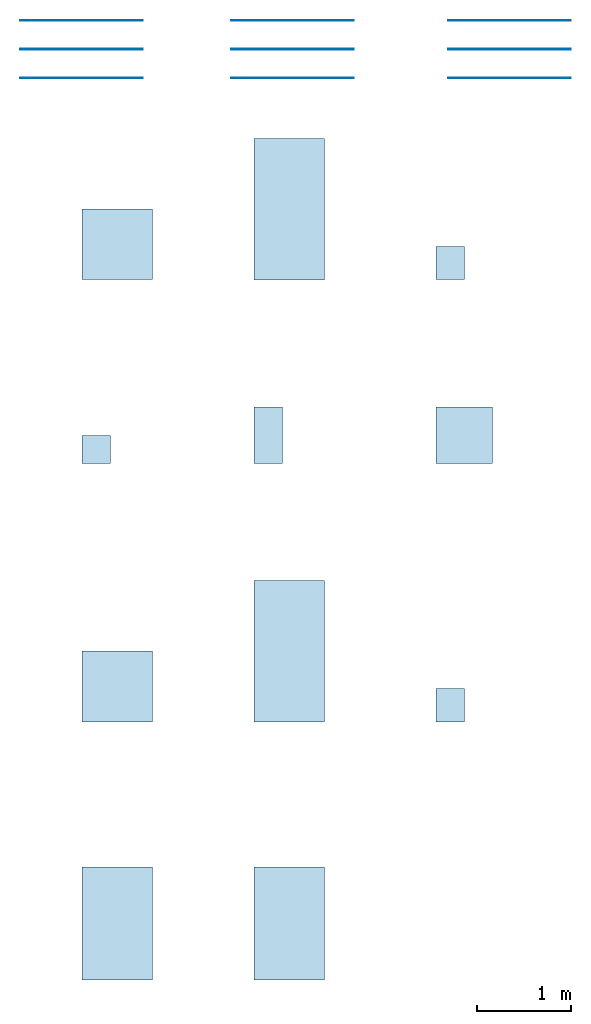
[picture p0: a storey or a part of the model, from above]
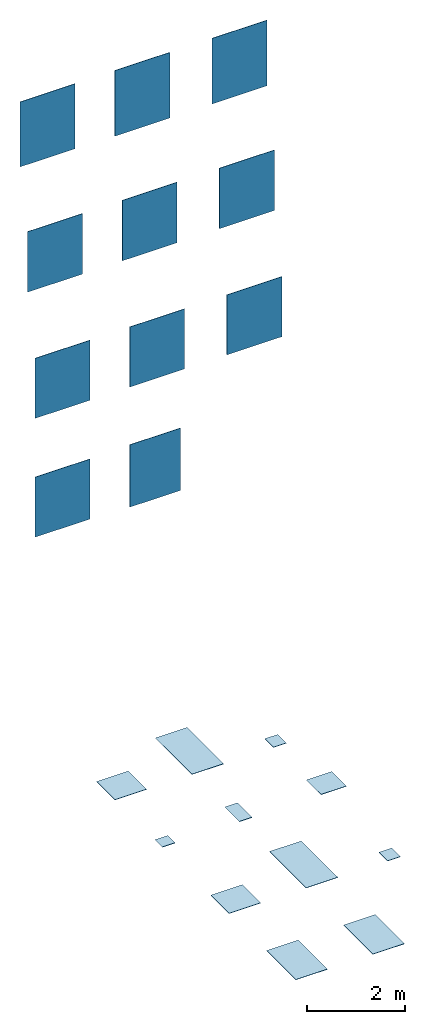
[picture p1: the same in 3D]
Properties of the parts of a building model (IFC2X3)

# File
Description: ViewDefinition [CoordinationView_V2.0], RevitIdentifiers [VersionGUID: 78f5554a-610e-4848-a1b2-b2670045736c, NumberOfSaves: 284], CoordinateReference [CoordinateBase: Shared Coordinates, ProjectSite: Internal]
File name: Project Number
Time: 2025-02-25T11:23:09+01:00
Written by: ODA SDAI 24.3
Made in: Autodesk Revit 24.1.11.26 (ENU) - IFC 24.1.11.26

# IfcProject, Project Number
LongName: Refin-Blended; Phase: Project Status

# IfcSite, Default
RefLatitude: 51, 30, 0, 549316; RefLongitude: 0, -7, -34, -450321; RefElevation: 0 mm

# IfcBuilding
Pset_BuildingCommon - NumberOfStoreys: 1

# IfcBuildingStorey: Level:Circle Head - Project Datum (2)
Pset_AirSideSystemInformation - sets with these values: 2
Name | LongName = Name | Elevation (mm)
Level 0 | Level 0 | 0
Level 1 | Level 1 | 4000

# IfcSlab: Floor:Floor_Tiles_Refin-Prestigio_Travertino-Bianco-Lucido-75x75 OO02, Floor:Floor_Tiles_Refin-Prestigio_Travertino-Bianco-Lucido-75x75 OO02:304668
In: Level 0
Type - PredefinedType: FLOOR; Material: Prestigio Travertino-Bianco-Lucido-75x75 OO02 9 mm, <Unnamed> 1 mm
Type - Pset_ConcreteElementGeneral - FireRating: INERT
Type - Pset_ElementShading - Color: WHITE
Type - Pset_FireRatingProperties - SurfaceSpreadOfFlame: INERT
Type - Pset_ManufacturerOccurrence - BarCode: N/A; SerialNumber: N/A
Type - Pset_ManufacturerTypeInformation - ArticleNumber: OO02; ModelReference: OO02; ModelLabel: BIANCO LUCIDO 75X75; Manufacturer: info@refin.it; ProductionYear: N/A
Type - Pset_PrecastConcreteElementGeneral - SerialNumber: N/A
Type - Pset_ProductRequirements - Name: Prestigio_Travertino_Bianco_Lucido_75X75; Category: Pr_35_93_96_19:Ceramic tiles
Type - Pset_QuantityTakeOff - Reference: N/A
Type - Pset_ReinforcementBarPitchOfSlab - Description: PORCELAIN STONEWARE TILE; Reference: N/A
Type - Pset_SlabCommon - Reference: N/A; IsExternal: no; AcousticRating: N/A; FireRating: INERT; SurfaceSpreadOfFlame: INERT
Type - Pset_Warranty - WarrantyContent: N/A; Exclusions: N/A
Pset_QuantityTakeOff - sets with these values: 2
Pset_SlabCommon - LoadBearing: no; PitchAngle: 0 deg

# IfcSlab: Floor:Floor_Tiles_Refin-Prestigio_Travertino-Bianco-Lucido-Mosaico-Cube 30.4x35.2 OO31, Floor:Floor_Tiles_Refin-Prestigio_Travertino-Bianco-Lucido-Mosaico-Cube 30.4x35.2 OO31:285295
In: Level 0
Type - PredefinedType: FLOOR; Material: Prestigio Travertino-Bianco-Lucido-Mosaico-Cube 30.4x35.2 OO31 9 mm, <Unnamed> 1 mm
Type - Pset_ConcreteElementGeneral - FireRating: INERT
Type - Pset_ElementShading - Color: WHITE
Type - Pset_FireRatingProperties - SurfaceSpreadOfFlame: INERT
Type - Pset_ManufacturerOccurrence - BarCode: N/A; SerialNumber: N/A
Type - Pset_ManufacturerTypeInformation - ArticleNumber: OO31; ModelReference: OO31; ModelLabel: BIANCO LUCIDO MOSAICO CUBE 30.4X35.2; Manufacturer: info@refin.it; ProductionYear: N/A
Type - Pset_PrecastConcreteElementGeneral - SerialNumber: N/A
Type - Pset_ProductRequirements - Name: Prestigio_Travertino_Bianco_Lucido_Mosaico_Cube_30.4X35.2; Category: Pr_35_93_96_19:Ceramic tiles
Type - Pset_QuantityTakeOff - Reference: N/A
Type - Pset_ReinforcementBarPitchOfSlab - Description: PORCELAIN STONEWARE TILE; Reference: N/A
Type - Pset_SlabCommon - Reference: N/A; IsExternal: no; AcousticRating: N/A; FireRating: INERT; SurfaceSpreadOfFlame: INERT
Type - Pset_Warranty - WarrantyContent: N/A; Exclusions: N/A
Pset_QuantityTakeOff - sets with these values: 2
Pset_SlabCommon - LoadBearing: no; PitchAngle: 0 deg

# IfcSlab: Floor:Floor_Tiles_Refin-Prestigio_Travertino-Bianco-Lucido-Mosaico-T 30x30 OO37, Floor:Floor_Tiles_Refin-Prestigio_Travertino-Bianco-Lucido-Mosaico-T 30x30 OO37:304956
In: Level 0
Type - PredefinedType: FLOOR; Material: Prestigio Travertino-Bianco-Mix-Mosaico-T 30x30 OO37 9 mm, <Unnamed> 1 mm
Type - Pset_ConcreteElementGeneral - FireRating: INERT
Type - Pset_ElementShading - Color: WHITE
Type - Pset_FireRatingProperties - SurfaceSpreadOfFlame: INERT
Type - Pset_ManufacturerOccurrence - BarCode: N/A; SerialNumber: N/A
Type - Pset_ManufacturerTypeInformation - ArticleNumber: OO37; ModelReference: OO37; ModelLabel: BIANCO MIX MOSAICO T 3X30; Manufacturer: info@refin.it; ProductionYear: N/A
Type - Pset_PrecastConcreteElementGeneral - SerialNumber: N/A
Type - Pset_ProductRequirements - Name: Prestigio_Travertino_Bianco_Mix_Mosaico_T_3X30; Category: Pr_35_93_96_19:Ceramic tiles
Type - Pset_QuantityTakeOff - Reference: N/A
Type - Pset_ReinforcementBarPitchOfSlab - Description: PORCELAIN STONEWARE TILE; Reference: N/A
Type - Pset_SlabCommon - Reference: N/A; IsExternal: no; AcousticRating: N/A; FireRating: INERT; SurfaceSpreadOfFlame: INERT
Type - Pset_Warranty - WarrantyContent: N/A; Exclusions: N/A
Pset_QuantityTakeOff - sets with these values: 2
Pset_SlabCommon - LoadBearing: no; PitchAngle: 0 deg

# IfcSlab: Floor:Floor_Tiles_Refin-Prestigio_Travertino-Bianco-Soft-30x60 OO08, Floor:Floor_Tiles_Refin-Prestigio_Travertino-Bianco-Soft-30x60 OO08:304948
In: Level 0
Type - PredefinedType: FLOOR; Material: Prestigio Travertino-Bianco-Soft-30x60 OO08 9 mm, <Unnamed> 1 mm
Type - Pset_ConcreteElementGeneral - FireRating: INERT
Type - Pset_ElementShading - Color: WHITE
Type - Pset_FireRatingProperties - SurfaceSpreadOfFlame: INERT
Type - Pset_ManufacturerOccurrence - BarCode: N/A; SerialNumber: N/A
Type - Pset_ManufacturerTypeInformation - ArticleNumber: OO08; ModelReference: OO08; ModelLabel: BIANCO SOFT 30X60; Manufacturer: info@refin.it; ProductionYear: N/A
Type - Pset_PrecastConcreteElementGeneral - SerialNumber: N/A
Type - Pset_ProductRequirements - Name: Prestigio_Travertino_Bianco_Soft_30X60; Category: Pr_35_93_96_19:Ceramic tiles
Type - Pset_QuantityTakeOff - Reference: N/A
Type - Pset_ReinforcementBarPitchOfSlab - Description: PORCELAIN STONEWARE TILE; Reference: N/A
Type - Pset_SlabCommon - Reference: N/A; IsExternal: no; AcousticRating: N/A; FireRating: INERT; SurfaceSpreadOfFlame: INERT
Type - Pset_Warranty - WarrantyContent: N/A; Exclusions: N/A
Pset_QuantityTakeOff - sets with these values: 2
Pset_SlabCommon - LoadBearing: no; PitchAngle: 0 deg

# IfcSlab: Floor:Floor_Tiles_Refin-Prestigio_Travertino-Bianco-Soft-60x120 OZ36, Floor:Floor_Tiles_Refin-Prestigio_Travertino-Bianco-Soft-60x120 OZ36:348918
In: Level 0
Type - PredefinedType: FLOOR; Material: Prestigio Travertino-Bianco-Soft-60x120 OZ36 9 mm, <Unnamed> 1 mm
Type - Pset_ConcreteElementGeneral - FireRating: INERT
Type - Pset_ElementShading - Color: WHITE
Type - Pset_FireRatingProperties - SurfaceSpreadOfFlame: INERT
Type - Pset_ManufacturerOccurrence - BarCode: N/A; SerialNumber: N/A
Type - Pset_ManufacturerTypeInformation - ArticleNumber: OZ36; ModelReference: OZ36; ModelLabel: BIANCO SOFT 60X120; Manufacturer: info@refin.it; ProductionYear: N/A
Type - Pset_PrecastConcreteElementGeneral - SerialNumber: N/A
Type - Pset_ProductRequirements - Name: Prestigio_Travertino_Bianco_Soft_60X120; Category: Pr_35_93_96_19:Ceramic tiles
Type - Pset_QuantityTakeOff - Reference: N/A
Type - Pset_ReinforcementBarPitchOfSlab - Description: PORCELAIN STONEWARE TILE; Reference: N/A
Type - Pset_SlabCommon - Reference: N/A; IsExternal: no; AcousticRating: N/A; FireRating: INERT; SurfaceSpreadOfFlame: INERT
Type - Pset_Warranty - WarrantyContent: N/A; Exclusions: N/A
Pset_QuantityTakeOff - sets with these values: 2
Pset_SlabCommon - LoadBearing: no; PitchAngle: 0 deg

# IfcSlab: Floor:Floor_Tiles_Refin-Prestigio_Travertino-Bianco-Soft-60x60 OO05, Floor:Floor_Tiles_Refin-Prestigio_Travertino-Bianco-Soft-60x60 OO05:304932
In: Level 0
Type - PredefinedType: FLOOR; Material: Prestigio Travertino-Bianco-Soft-60x60 OO05 9 mm, <Unnamed> 1 mm
Type - Pset_ConcreteElementGeneral - FireRating: INERT
Type - Pset_ElementShading - Color: WHITE
Type - Pset_FireRatingProperties - SurfaceSpreadOfFlame: INERT
Type - Pset_ManufacturerOccurrence - BarCode: N/A; SerialNumber: N/A
Type - Pset_ManufacturerTypeInformation - ArticleNumber: OO05; ModelReference: OO05; ModelLabel: BIANCO SOFT 60X60; Manufacturer: info@refin.it; ProductionYear: N/A
Type - Pset_PrecastConcreteElementGeneral - SerialNumber: N/A
Type - Pset_ProductRequirements - Name: Prestigio_Travertino_Bianco_Soft_60X60; Category: Pr_35_93_96_19:Ceramic tiles
Type - Pset_QuantityTakeOff - Reference: N/A
Type - Pset_ReinforcementBarPitchOfSlab - Description: PORCELAIN STONEWARE TILE; Reference: N/A
Type - Pset_SlabCommon - Reference: N/A; IsExternal: no; AcousticRating: N/A; FireRating: INERT; SurfaceSpreadOfFlame: INERT
Type - Pset_Warranty - WarrantyContent: N/A; Exclusions: N/A
Pset_QuantityTakeOff - sets with these values: 2
Pset_SlabCommon - LoadBearing: no; PitchAngle: 0 deg

# IfcSlab: Floor:Floor_Tiles_Refin-Prestigio_Travertino-Bianco-Soft-75x150 OM84, Floor:Floor_Tiles_Refin-Prestigio_Travertino-Bianco-Soft-75x150 OM84:339635
In: Level 0
Type - PredefinedType: FLOOR; Material: Prestigio Travertino-Bianco-Soft-75x150 OM84 9 mm, <Unnamed> 1 mm
Type - Pset_ConcreteElementGeneral - FireRating: INERT
Type - Pset_ElementShading - Color: WHITE
Type - Pset_FireRatingProperties - SurfaceSpreadOfFlame: INERT
Type - Pset_ManufacturerOccurrence - BarCode: N/A; SerialNumber: N/A
Type - Pset_ManufacturerTypeInformation - ArticleNumber: OM84; ModelReference: OM84; ModelLabel: BIANCO SOFT 75X150; Manufacturer: info@refin.it; ProductionYear: N/A
Type - Pset_PrecastConcreteElementGeneral - SerialNumber: N/A
Type - Pset_ProductRequirements - Name: Prestigio_Travertino_Bianco_Soft_75X150; Category: Pr_35_93_96_19:Ceramic tiles
Type - Pset_QuantityTakeOff - Reference: N/A
Type - Pset_ReinforcementBarPitchOfSlab - Description: PORCELAIN STONEWARE TILE; Reference: N/A
Type - Pset_SlabCommon - Reference: N/A; IsExternal: no; AcousticRating: N/A; FireRating: INERT; SurfaceSpreadOfFlame: INERT
Type - Pset_Warranty - WarrantyContent: N/A; Exclusions: N/A
Pset_QuantityTakeOff - sets with these values: 2
Pset_SlabCommon - LoadBearing: no; PitchAngle: 0 deg

# IfcSlab: Floor:Floor_Tiles_Refin-Prestigio_Travertino-Bianco-Soft-75x150 OM87, Floor:Floor_Tiles_Refin-Prestigio_Travertino-Bianco-Soft-75x150 OM87:324498
In: Level 0
Type - PredefinedType: FLOOR; Material: Prestigio Travertino-Bianco-Lucido-75x150 OM87 9 mm, <Unnamed> 1 mm
Type - Pset_ConcreteElementGeneral - FireRating: INERT
Type - Pset_ElementShading - Color: WHITE
Type - Pset_FireRatingProperties - SurfaceSpreadOfFlame: INERT
Type - Pset_ManufacturerOccurrence - BarCode: N/A; SerialNumber: N/A
Type - Pset_ManufacturerTypeInformation - ArticleNumber: OM87; ModelReference: OM87; ModelLabel: BIANCO LUCIDO 75X150; Manufacturer: info@refin.it; ProductionYear: N/A
Type - Pset_PrecastConcreteElementGeneral - SerialNumber: N/A
Type - Pset_ProductRequirements - Name: Prestigio_Travertino_Bianco_Lucido_75X150; Category: Pr_35_93_96_19:Ceramic tiles
Type - Pset_QuantityTakeOff - Reference: N/A
Type - Pset_ReinforcementBarPitchOfSlab - Description: PORCELAIN STONEWARE TILE; Reference: N/A
Type - Pset_SlabCommon - Reference: N/A; IsExternal: no; AcousticRating: N/A; FireRating: INERT; SurfaceSpreadOfFlame: INERT
Type - Pset_Warranty - WarrantyContent: N/A; Exclusions: N/A
Pset_QuantityTakeOff - sets with these values: 2
Pset_SlabCommon - LoadBearing: no; PitchAngle: 0 deg

# IfcSlab: Floor:Floor_Tiles_Refin-Prestigio_Travertino-Bianco-Soft-75x75 ON99, Floor:Floor_Tiles_Refin-Prestigio_Travertino-Bianco-Soft-75x75 ON99:305509
In: Level 0
Type - PredefinedType: FLOOR; Material: Prestigio Travertino-Bianco-Soft-75x75 ON99 9 mm, <Unnamed> 1 mm
Type - Pset_ConcreteElementGeneral - FireRating: INERT
Type - Pset_ElementShading - Color: WHITE
Type - Pset_FireRatingProperties - SurfaceSpreadOfFlame: INERT
Type - Pset_ManufacturerOccurrence - BarCode: N/A; SerialNumber: N/A
Type - Pset_ManufacturerTypeInformation - ArticleNumber: ON99; ModelReference: ON99; ModelLabel: BIANCO SOFT 75X75; Manufacturer: info@refin.it; ProductionYear: N/A
Type - Pset_PrecastConcreteElementGeneral - SerialNumber: N/A
Type - Pset_ProductRequirements - Name: Prestigio_Travertino_Bianco_Soft_75X75; Category: Pr_35_93_96_19:Ceramic tiles
Type - Pset_QuantityTakeOff - Reference: N/A
Type - Pset_ReinforcementBarPitchOfSlab - Description: PORCELAIN STONEWARE TILE; Reference: N/A
Type - Pset_SlabCommon - Reference: N/A; IsExternal: no; AcousticRating: N/A; FireRating: INERT; SurfaceSpreadOfFlame: INERT
Type - Pset_Warranty - WarrantyContent: N/A; Exclusions: N/A
Pset_QuantityTakeOff - sets with these values: 2
Pset_SlabCommon - LoadBearing: no; PitchAngle: 0 deg

# IfcSlab: Floor:Floor_Tiles_Refin-Prestigio_Travertino-Bianco-Soft-Mosaico-Cube 30.4x35.2 OO34, Floor:Floor_Tiles_Refin-Prestigio_Travertino-Bianco-Soft-Mosaico-Cube 30.4x35.2 OO34:339650
In: Level 0
Type - PredefinedType: FLOOR; Material: Prestigio Travertino-Bianco-Soft-Mosaico-Cube 30.4x35.2 OO34 9 mm, <Unnamed> 1 mm
Type - Pset_ConcreteElementGeneral - FireRating: INERT
Type - Pset_ElementShading - Color: WHITE
Type - Pset_FireRatingProperties - SurfaceSpreadOfFlame: INERT
Type - Pset_ManufacturerOccurrence - BarCode: N/A; SerialNumber: N/A
Type - Pset_ManufacturerTypeInformation - ArticleNumber: OO34; ModelReference: OO34; ModelLabel: BIANCO SOFT MOSAICO CUBE 30.4X35.2; Manufacturer: info@refin.it; ProductionYear: N/A
Type - Pset_PrecastConcreteElementGeneral - SerialNumber: N/A
Type - Pset_ProductRequirements - Name: Prestigio_Travertino_Bianco_Soft_Mosaico_Cube_30.4X35.2; Category: Pr_35_93_96_19:Ceramic tiles
Type - Pset_QuantityTakeOff - Reference: N/A
Type - Pset_ReinforcementBarPitchOfSlab - Description: PORCELAIN STONEWARE TILE; Reference: N/A
Type - Pset_SlabCommon - Reference: N/A; IsExternal: no; AcousticRating: N/A; FireRating: INERT; SurfaceSpreadOfFlame: INERT
Type - Pset_Warranty - WarrantyContent: N/A; Exclusions: N/A
Pset_QuantityTakeOff - sets with these values: 2
Pset_SlabCommon - LoadBearing: no; PitchAngle: 0 deg

# IfcSlab: Floor:Floor_Tiles_Refin-Prestigio_Travertino-Dorico-Bianco-60x120 OZ79, Floor:Floor_Tiles_Refin-Prestigio_Travertino-Dorico-Bianco-60x120 OZ79:349322
In: Level 0
Type - PredefinedType: FLOOR; Material: Prestigio Travertino-Dorico-Bianco-60x120 OZ79 9 mm, <Unnamed> 1 mm
Type - Pset_ConcreteElementGeneral - FireRating: INERT
Type - Pset_ElementShading - Color: WHITE
Type - Pset_FireRatingProperties - SurfaceSpreadOfFlame: INERT
Type - Pset_ManufacturerOccurrence - BarCode: N/A; SerialNumber: N/A
Type - Pset_ManufacturerTypeInformation - ArticleNumber: OZ79; ModelReference: OZ79; ModelLabel: DORICO BIANCO 60X120; Manufacturer: info@refin.it; ProductionYear: N/A
Type - Pset_PrecastConcreteElementGeneral - SerialNumber: N/A
Type - Pset_ProductRequirements - Name: Prestigio_Travertino_Dorico_Bianco_60X120; Category: Pr_35_93_96_19:Ceramic tiles
Type - Pset_QuantityTakeOff - Reference: N/A
Type - Pset_ReinforcementBarPitchOfSlab - Description: PORCELAIN STONEWARE TILE; Reference: N/A
Type - Pset_SlabCommon - Reference: N/A; IsExternal: no; AcousticRating: N/A; FireRating: INERT; SurfaceSpreadOfFlame: INERT
Type - Pset_Warranty - WarrantyContent: N/A; Exclusions: N/A
Pset_QuantityTakeOff - sets with these values: 2
Pset_SlabCommon - LoadBearing: no; PitchAngle: 0 deg

# IfcWallStandardCase: Basic Wall:Floor_Tiles_Refin-Prestigio_Travertino-Bianco-Lucido-75x150 OM87, Basic Wall:Floor_Tiles_Refin-Prestigio_Travertino-Bianco-Lucido-75x150 OM87:333696
In: Level 0
Type - PredefinedType: STANDARD; Material: <Unnamed> 1 mm, Prestigio Travertino-Bianco-Lucido-75x150 OM87 9 mm
Type - Pset_ElementShading - Color: WHITE
Type - Pset_FireRatingProperties - SurfaceSpreadOfFlame: INERT
Type - Pset_ManufacturerOccurrence - BarCode: N/A; SerialNumber: N/A
Type - Pset_ManufacturerTypeInformation - ArticleNumber: OM87; ModelReference: OM87; ModelLabel: BIANCO LUCIDO 75X150; Manufacturer: info@refin.it; ProductionYear: N/A
Type - Pset_PrecastConcreteElementGeneral - SerialNumber: N/A
Type - Pset_ProductRequirements - Name: Prestigio Travertino_Bianco_Lucido_75X150; Category: Pr_35_93_96_19:Ceramic tiles
Type - Pset_QuantityTakeOff - Reference: N/A
Type - Pset_ReinforcementBarPitchOfWall - Description: PORCELAIN STONEWARE TILE; Reference: N/A
Type - Pset_WallCommon - Reference: N/A; IsExternal: no; AcousticRating: N/A; SurfaceSpreadOfFlame: INERT
Type - Pset_Warranty - WarrantyContent: N/A; Exclusions: N/A
Pset_QuantityTakeOff - sets with these values: 2
Pset_WallCommon - LoadBearing: no; ExtendToStructure: no

# IfcWallStandardCase: Basic Wall:Floor_Tiles_Refin-Prestigio_Travertino-Bianco-Lucido-75x75 OO02, Basic Wall:Floor_Tiles_Refin-Prestigio_Travertino-Bianco-Lucido-75x75 OO02:334895
In: Level 0
Type - PredefinedType: STANDARD; Material: <Unnamed> 1 mm, Prestigio Travertino-Bianco-Lucido-75x75 OO02 9 mm
Type - Pset_ElementShading - Color: WHITE
Type - Pset_FireRatingProperties - SurfaceSpreadOfFlame: INERT
Type - Pset_ManufacturerOccurrence - BarCode: N/A; SerialNumber: N/A
Type - Pset_ManufacturerTypeInformation - ArticleNumber: OO02; ModelReference: OO02; ModelLabel: BIANCO LUCIDO 75X75; Manufacturer: info@refin.it; ProductionYear: N/A
Type - Pset_PrecastConcreteElementGeneral - SerialNumber: N/A
Type - Pset_ProductRequirements - Name: Prestigio Travertino_Bianco_Lucido_75X75; Category: Pr_35_93_96_19:Ceramic tiles
Type - Pset_QuantityTakeOff - Reference: N/A
Type - Pset_ReinforcementBarPitchOfWall - Description: PORCELAIN STONEWARE TILE; Reference: N/A
Type - Pset_WallCommon - Reference: N/A; IsExternal: no; AcousticRating: N/A; SurfaceSpreadOfFlame: INERT
Type - Pset_Warranty - WarrantyContent: N/A; Exclusions: N/A
Pset_QuantityTakeOff - sets with these values: 2
Pset_WallCommon - LoadBearing: no; ExtendToStructure: no

# IfcWallStandardCase: Basic Wall:Floor_Tiles_Refin-Prestigio_Travertino-Bianco-Lucido-Mosaico-Cube 30.4x35.2 OO31, Basic Wall:Floor_Tiles_Refin-Prestigio_Travertino-Bianco-Lucido-Mosaico-Cube 30.4x35.2 OO31:334553
In: Level 0
Type - PredefinedType: STANDARD; Material: <Unnamed> 1 mm, Prestigio Travertino-Bianco-Lucido-Mosaico-Cube 30.4x35.2 OO31 9 mm
Type - Pset_ElementShading - Color: WHITE
Type - Pset_FireRatingProperties - SurfaceSpreadOfFlame: INERT
Type - Pset_ManufacturerOccurrence - BarCode: N/A; SerialNumber: N/A
Type - Pset_ManufacturerTypeInformation - ArticleNumber: OO31; ModelReference: OO31; ModelLabel: BIANCO LUCIDO MOSAICO CUBE 30.4X35.2; Manufacturer: info@refin.it; ProductionYear: N/A
Type - Pset_PrecastConcreteElementGeneral - SerialNumber: N/A
Type - Pset_ProductRequirements - Name: Prestigio Travertino_Bianco_Lucido_Mosaico_Cube_30.4X35.2; Category: Pr_35_93_96_19:Ceramic tiles
Type - Pset_QuantityTakeOff - Reference: N/A
Type - Pset_ReinforcementBarPitchOfWall - Description: PORCELAIN STONEWARE TILE; Reference: N/A
Type - Pset_WallCommon - Reference: N/A; IsExternal: no; AcousticRating: N/A; SurfaceSpreadOfFlame: INERT
Type - Pset_Warranty - WarrantyContent: N/A; Exclusions: N/A
Pset_QuantityTakeOff - sets with these values: 2
Pset_WallCommon - LoadBearing: no; ExtendToStructure: no

# IfcWallStandardCase: Basic Wall:Floor_Tiles_Refin-Prestigio_Travertino-Bianco-Lucido-Mosaico-T 30x30 OO37, Basic Wall:Floor_Tiles_Refin-Prestigio_Travertino-Bianco-Lucido-Mosaico-T 30x30 OO37:335038
In: Level 0
Type - PredefinedType: STANDARD; Material: <Unnamed> 1 mm, Prestigio Travertino-Bianco-Mix-Mosaico-T 30x30 OO37 9 mm
Type - Pset_ElementShading - Color: WHITE
Type - Pset_FireRatingProperties - SurfaceSpreadOfFlame: INERT
Type - Pset_ManufacturerOccurrence - BarCode: N/A; SerialNumber: N/A
Type - Pset_ManufacturerTypeInformation - ArticleNumber: OO37; ModelReference: OO37; ModelLabel: BIANCO MIX MOSAICO T 30X30; Manufacturer: info@refin.it; ProductionYear: N/A
Type - Pset_PrecastConcreteElementGeneral - SerialNumber: N/A
Type - Pset_ProductRequirements - Name: Prestigio Travertino_Bianco_Mix_Mosaico_T_30X30; Category: Pr_35_93_96_19:Ceramic tiles
Type - Pset_QuantityTakeOff - Reference: N/A
Type - Pset_ReinforcementBarPitchOfWall - Description: PORCELAIN STONEWARE TILE; Reference: N/A
Type - Pset_WallCommon - Reference: N/A; IsExternal: no; AcousticRating: N/A; SurfaceSpreadOfFlame: INERT
Type - Pset_Warranty - WarrantyContent: N/A; Exclusions: N/A
Pset_QuantityTakeOff - sets with these values: 2
Pset_WallCommon - LoadBearing: no; ExtendToStructure: no

# IfcWallStandardCase: Basic Wall:Floor_Tiles_Refin-Prestigio_Travertino-Bianco-Soft-30x60 OO08, Basic Wall:Floor_Tiles_Refin-Prestigio_Travertino-Bianco-Soft-30x60 OO08:335490
In: Level 0
Type - PredefinedType: STANDARD; Material: <Unnamed> 1 mm, Prestigio Travertino-Bianco-Soft-30x60 OO08 9 mm
Type - Pset_ElementShading - Color: WHITE
Type - Pset_FireRatingProperties - SurfaceSpreadOfFlame: INERT
Type - Pset_ManufacturerOccurrence - BarCode: N/A; SerialNumber: N/A
Type - Pset_ManufacturerTypeInformation - ArticleNumber: OO08; ModelReference: OO08; ModelLabel: BIANCO SOFT 30X60; Manufacturer: info@refin.it; ProductionYear: N/A
Type - Pset_PrecastConcreteElementGeneral - SerialNumber: N/A
Type - Pset_ProductRequirements - Name: Prestigio Travertino_Bianco_Soft_30X60; Category: Pr_35_93_96_19:Ceramic tiles
Type - Pset_QuantityTakeOff - Reference: N/A
Type - Pset_ReinforcementBarPitchOfWall - Description: PORCELAIN STONEWARE TILE; Reference: N/A
Type - Pset_WallCommon - Reference: N/A; IsExternal: no; AcousticRating: N/A; SurfaceSpreadOfFlame: INERT
Type - Pset_Warranty - WarrantyContent: N/A; Exclusions: N/A
Pset_QuantityTakeOff - sets with these values: 2
Pset_WallCommon - LoadBearing: no; ExtendToStructure: no

# IfcWallStandardCase: Basic Wall:Floor_Tiles_Refin-Prestigio_Travertino-Bianco-Soft-60x120 OZ36, Basic Wall:Floor_Tiles_Refin-Prestigio_Travertino-Bianco-Soft-60x120 OZ36:348957
In: Level 0
Type - PredefinedType: STANDARD; Material: <Unnamed> 1 mm, Prestigio Travertino-Bianco-Soft-60x120 OZ36 9 mm
Type - Pset_ElementShading - Color: WHITE
Type - Pset_FireRatingProperties - SurfaceSpreadOfFlame: INERT
Type - Pset_ManufacturerOccurrence - BarCode: N/A; SerialNumber: N/A
Type - Pset_ManufacturerTypeInformation - ArticleNumber: OZ36; ModelReference: OZ36; ModelLabel: BIANCO SOFT 60X120; Manufacturer: info@refin.it; ProductionYear: N/A
Type - Pset_PrecastConcreteElementGeneral - SerialNumber: N/A
Type - Pset_ProductRequirements - Name: Prestigio Travertino_Bianco_Soft_60X120; Category: Pr_35_93_96_19:Ceramic tiles
Type - Pset_QuantityTakeOff - Reference: N/A
Type - Pset_ReinforcementBarPitchOfWall - Description: PORCELAIN STONEWARE TILE; Reference: N/A
Type - Pset_WallCommon - Reference: N/A; IsExternal: no; AcousticRating: N/A; SurfaceSpreadOfFlame: INERT
Type - Pset_Warranty - WarrantyContent: N/A; Exclusions: N/A
Pset_QuantityTakeOff - sets with these values: 2
Pset_WallCommon - LoadBearing: no; ExtendToStructure: no

# IfcWallStandardCase: Basic Wall:Floor_Tiles_Refin-Prestigio_Travertino-Bianco-Soft-60x60 OO05, Basic Wall:Floor_Tiles_Refin-Prestigio_Travertino-Bianco-Soft-60x60 OO05:335882
In: Level 0
Type - PredefinedType: STANDARD; Material: <Unnamed> 1 mm, Prestigio Travertino-Bianco-Soft-60x60 OO05 9 mm
Type - Pset_ElementShading - Color: WHITE
Type - Pset_FireRatingProperties - SurfaceSpreadOfFlame: INERT
Type - Pset_ManufacturerOccurrence - BarCode: N/A; SerialNumber: N/A
Type - Pset_ManufacturerTypeInformation - ArticleNumber: OO05; ModelReference: OO05; ModelLabel: BIANCO SOFT 60X60; Manufacturer: info@refin.it; ProductionYear: N/A
Type - Pset_PrecastConcreteElementGeneral - SerialNumber: N/A
Type - Pset_ProductRequirements - Name: Prestigio Travertino_Bianco_Soft_60X60; Category: Pr_35_93_96_19:Ceramic tiles
Type - Pset_QuantityTakeOff - Reference: N/A
Type - Pset_ReinforcementBarPitchOfWall - Description: PORCELAIN STONEWARE TILE; Reference: N/A
Type - Pset_WallCommon - Reference: N/A; IsExternal: no; AcousticRating: N/A; SurfaceSpreadOfFlame: INERT
Type - Pset_Warranty - WarrantyContent: N/A; Exclusions: N/A
Pset_QuantityTakeOff - sets with these values: 2
Pset_WallCommon - LoadBearing: no; ExtendToStructure: no

# IfcWallStandardCase: Basic Wall:Floor_Tiles_Refin-Prestigio_Travertino-Bianco-Soft-75x150 OM84, Basic Wall:Floor_Tiles_Refin-Prestigio_Travertino-Bianco-Soft-75x150 OM84:339715
In: Level 0
Type - PredefinedType: STANDARD; Material: <Unnamed> 1 mm, Prestigio Travertino-Bianco-Soft-75x150 OM84 9 mm
Type - Pset_ElementShading - Color: WHITE
Type - Pset_FireRatingProperties - SurfaceSpreadOfFlame: INERT
Type - Pset_ManufacturerOccurrence - BarCode: N/A; SerialNumber: N/A
Type - Pset_ManufacturerTypeInformation - ArticleNumber: OM84; ModelReference: OM84; ModelLabel: BIANCO SOFT 75X150; Manufacturer: info@refin.it; ProductionYear: N/A
Type - Pset_PrecastConcreteElementGeneral - SerialNumber: N/A
Type - Pset_ProductRequirements - Name: Prestigio Travertino_Bianco_Soft_75X150; Category: Pr_35_93_96_19:Ceramic tiles
Type - Pset_QuantityTakeOff - Reference: N/A
Type - Pset_ReinforcementBarPitchOfWall - Description: PORCELAIN STONEWARE TILE; Reference: N/A
Type - Pset_WallCommon - Reference: N/A; IsExternal: no; AcousticRating: N/A; SurfaceSpreadOfFlame: INERT
Type - Pset_Warranty - WarrantyContent: N/A; Exclusions: N/A
Pset_QuantityTakeOff - sets with these values: 2
Pset_WallCommon - LoadBearing: no; ExtendToStructure: no

# IfcWallStandardCase: Basic Wall:Floor_Tiles_Refin-Prestigio_Travertino-Bianco-Soft-75x75 ON99, Basic Wall:Floor_Tiles_Refin-Prestigio_Travertino-Bianco-Soft-75x75 ON99:336183
In: Level 0
Type - PredefinedType: STANDARD; Material: <Unnamed> 1 mm, Prestigio Travertino-Bianco-Soft-75x75 ON99 9 mm
Type - Pset_ElementShading - Color: WHITE
Type - Pset_FireRatingProperties - SurfaceSpreadOfFlame: INERT
Type - Pset_ManufacturerOccurrence - BarCode: N/A; SerialNumber: N/A
Type - Pset_ManufacturerTypeInformation - ArticleNumber: ON99; ModelReference: ON99; ModelLabel: BIANCO SOFT 75X75; Manufacturer: info@refin.it; ProductionYear: N/A
Type - Pset_PrecastConcreteElementGeneral - SerialNumber: N/A
Type - Pset_ProductRequirements - Name: Prestigio Travertino_Bianco_Soft_75X75; Category: Pr_35_93_96_19:Ceramic tiles
Type - Pset_QuantityTakeOff - Reference: N/A
Type - Pset_ReinforcementBarPitchOfWall - Description: PORCELAIN STONEWARE TILE; Reference: N/A
Type - Pset_WallCommon - Reference: N/A; IsExternal: no; AcousticRating: N/A; SurfaceSpreadOfFlame: INERT
Type - Pset_Warranty - WarrantyContent: N/A; Exclusions: N/A
Pset_QuantityTakeOff - sets with these values: 2
Pset_WallCommon - LoadBearing: no; ExtendToStructure: no

# IfcWallStandardCase: Basic Wall:Floor_Tiles_Refin-Prestigio_Travertino-Bianco-Soft-Mosaico-Cube 30.4x35.2 OO34, Basic Wall:Floor_Tiles_Refin-Prestigio_Travertino-Bianco-Soft-Mosaico-Cube 30.4x35.2 OO34:339723
In: Level 0
Type - PredefinedType: STANDARD; Material: <Unnamed> 1 mm, Prestigio Travertino-Bianco-Soft-Mosaico-Cube 30.4x35.2 OO34 9 mm
Type - Pset_ElementShading - Color: WHITE
Type - Pset_FireRatingProperties - SurfaceSpreadOfFlame: INERT
Type - Pset_ManufacturerOccurrence - BarCode: N/A; SerialNumber: N/A
Type - Pset_ManufacturerTypeInformation - ArticleNumber: OO34; ModelReference: OO34; ModelLabel: BIANCO SOFT MOSAICO CUBE 30.4X35.2; Manufacturer: info@refin.it; ProductionYear: N/A
Type - Pset_PrecastConcreteElementGeneral - SerialNumber: N/A
Type - Pset_ProductRequirements - Name: Prestigio Travertino_Bianco_Soft_Mosaico_Cube_30.4X35.2; Category: Pr_35_93_96_19:Ceramic tiles
Type - Pset_QuantityTakeOff - Reference: N/A
Type - Pset_ReinforcementBarPitchOfWall - Description: PORCELAIN STONEWARE TILE; Reference: N/A
Type - Pset_WallCommon - Reference: N/A; IsExternal: no; AcousticRating: N/A; SurfaceSpreadOfFlame: INERT
Type - Pset_Warranty - WarrantyContent: N/A; Exclusions: N/A
Pset_QuantityTakeOff - sets with these values: 2
Pset_WallCommon - LoadBearing: no; ExtendToStructure: no

# IfcWallStandardCase: Basic Wall:Floor_Tiles_Refin-Prestigio_Travertino-Dorico-Bianco-60x120 OZ79, Basic Wall:Floor_Tiles_Refin-Prestigio_Travertino-Dorico-Bianco-60x120 OZ79:349395
In: Level 0
Type - PredefinedType: STANDARD; Material: <Unnamed> 1 mm, Prestigio Travertino-Dorico-Bianco-60x120 OZ79 9 mm
Type - Pset_ElementShading - Color: WHITE
Type - Pset_FireRatingProperties - SurfaceSpreadOfFlame: INERT
Type - Pset_ManufacturerOccurrence - BarCode: N/A; SerialNumber: N/A
Type - Pset_ManufacturerTypeInformation - ArticleNumber: OZ79; ModelReference: OZ79; ModelLabel: DORICO BIANCO 60X120; Manufacturer: info@refin.it; ProductionYear: N/A
Type - Pset_PrecastConcreteElementGeneral - SerialNumber: N/A
Type - Pset_ProductRequirements - Name: Prestigio_Travertino_Dorico_Bianco_60X120; Category: Pr_35_93_96_19:Ceramic tiles
Type - Pset_QuantityTakeOff - Reference: N/A
Type - Pset_ReinforcementBarPitchOfWall - Description: PORCELAIN STONEWARE TILE; Reference: N/A
Type - Pset_WallCommon - Reference: N/A; IsExternal: no; AcousticRating: N/A; SurfaceSpreadOfFlame: INERT
Type - Pset_Warranty - WarrantyContent: N/A; Exclusions: N/A
Pset_QuantityTakeOff - sets with these values: 2
Pset_WallCommon - LoadBearing: no; ExtendToStructure: no
